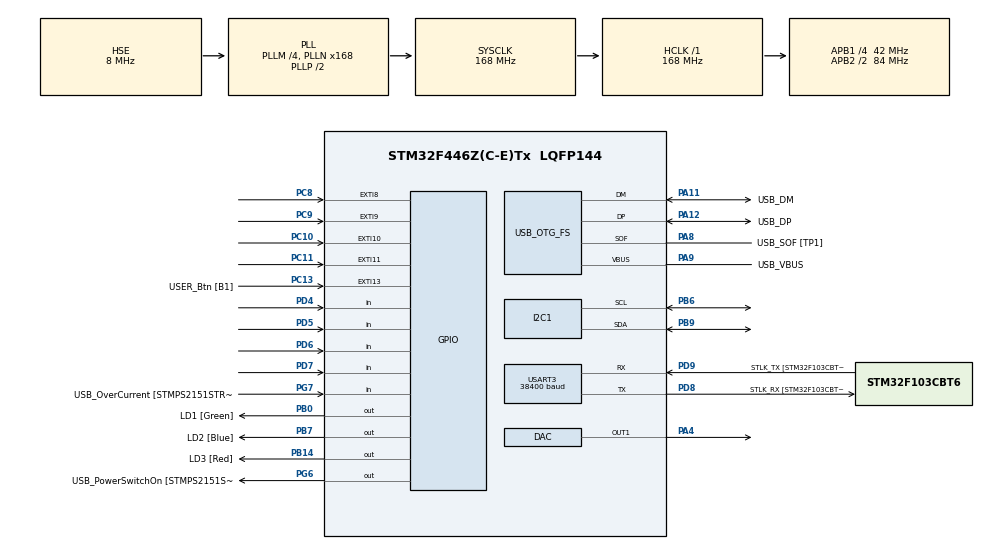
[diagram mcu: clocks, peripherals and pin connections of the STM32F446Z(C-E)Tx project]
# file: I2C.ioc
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Mcu.Family=STM32F4
Mcu.Name=STM32F446Z(C-E)Tx
Mcu.Package=LQFP144
NVIC.PriorityGroup=NVIC_PRIORITYGROUP_4
PA10.GPIO_Label=USB_ID
PA10.Signal=USB_OTG_FS_ID
PA11.GPIO_Label=USB_DM
PA11.Mode=Device_Only
PA11.Signal=USB_OTG_FS_DM
PA12.GPIO_Label=USB_DP
PA12.Mode=Device_Only
PA12.Signal=USB_OTG_FS_DP
PA13.GPIO_Label=TMS
PA13.Mode=Serial_Wire
PA13.Signal=SYS_JTMS-SWDIO
PA14.GPIO_Label=TCK
PA14.Mode=Serial_Wire
PA14.Signal=SYS_JTCK-SWCLK
PA4.Signal=COMP_DAC1_group
PA8.GPIO_Label=USB_SOF [TP1]
PA8.Mode=Activate_SOF_FS
PA8.Signal=USB_OTG_FS_SOF
PA9.GPIO_Label=USB_VBUS
PA9.Mode=Activate_VBUS
PA9.Signal=USB_OTG_FS_VBUS
PB0.GPIO_Label=LD1 [Green]
PB0.Signal=GPIO_Output
PB14.GPIO_Label=LD3 [Red]
PB14.Signal=GPIO_Output
PB6.Mode=I2C
PB6.Signal=I2C1_SCL
PB7.GPIO_Label=LD2 [Blue]
PB7.Signal=GPIO_Output
PB9.Mode=I2C
PB9.Signal=I2C1_SDA
PC10.Signal=GPXTI10
PC11.Signal=GPXTI11
PC13.GPIO_Label=USER_Btn [B1]
PC13.Signal=GPXTI13
PC14-OSC32_IN.Mode=LSE-External-Oscillator
PC14-OSC32_IN.Signal=RCC_OSC32_IN
PC15-OSC32_OUT.Mode=LSE-External-Oscillator
PC15-OSC32_OUT.Signal=RCC_OSC32_OUT
PC8.Signal=GPXTI8
PC9.Signal=GPXTI9
PD4.Signal=GPIO_Input
PD5.Signal=GPIO_Input
PD6.Signal=GPIO_Input
PD7.Signal=GPIO_Input
PD8.GPIO_Label=STLK_RX [STM32F103CBT6_PA3]
PD8.Mode=Asynchronous
PD8.Signal=USART3_TX
PD9.GPIO_Label=STLK_TX [STM32F103CBT6_PA2]
PD9.Mode=Asynchronous
PD9.Signal=USART3_RX
PG6.GPIO_Label=USB_PowerSwitchOn [STMPS2151STR_EN]
PG6.Signal=GPIO_Output
PG7.GPIO_Label=USB_OverCurrent [STMPS2151STR_FAULT]
PG7.Signal=GPIO_Input
PH0-OSC_IN.GPIO_Label=MCO [STM32F103CBT6_PA8]
PH0-OSC_IN.Mode=HSE-External-Clock-Source
PH0-OSC_IN.Signal=RCC_OSC_IN
PH1-OSC_OUT.Mode=HSE-External-Clock-Source
PH1-OSC_OUT.Signal=RCC_OSC_OUT
ProjectManager.HeapSize=0x200
ProjectManager.StackSize=0x400
ProjectManager.TargetToolchain=STM32CubeIDE
RCC.48MHZClocksFreq_Value=24000000
RCC.AHBFreq_Value=168000000
RCC.APB1CLKDivider=RCC_HCLK_DIV4
RCC.APB1Freq_Value=42000000
RCC.APB1TimFreq_Value=84000000
RCC.APB2CLKDivider=RCC_HCLK_DIV2
RCC.APB2Freq_Value=84000000
RCC.APB2TimFreq_Value=168000000
RCC.CortexFreq_Value=168000000
RCC.HCLKFreq_Value=168000000
RCC.HSE_VALUE=8000000
RCC.HSI_VALUE=16000000
RCC.PLLM=4
RCC.PLLMUL=RCC_PLL_MUL9
RCC.PLLN=168
RCC.PLLQ=7
RCC.PRESCALERUSB=RCC_USBCLKSOURCE_PLL_DIV1_5
RCC.SYSCLKFreq_VALUE=168000000
RCC.SYSCLKSource=RCC_SYSCLKSOURCE_PLLCLK
RCC.SYSCLKSourceVirtual=RCC_SYSCLKSOURCE_PLLCLK
RCC.USBFreq_Value=48000000
RCC.VCOOutputFreq_Value=336000000
SH.COMP_DAC1_group.0=DAC_OUT1,DAC_OUT1
USART3.BaudRate=38400
USART3.VirtualMode=VM_ASYNC
USB_OTG_FS.VirtualMode=Device_Only
VP_TIM6_VS_ClockSourceINT.Mode=Enable_Timer
board=NUCLEO-F446ZE

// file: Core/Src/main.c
/* USER CODE BEGIN Header */
/**
  ******************************************************************************
  * @file           : main.c
  * @brief          : Main program body
  ******************************************************************************
  * @attention
  *
  * Copyright (c) 2025 STMicroelectronics.
  * All rights reserved.
  *
  * This software is licensed under terms that can be found in the LICENSE file
  * in the root directory of this software component.
  * If no LICENSE file comes with this software, it is provided AS-IS.
  *
  ******************************************************************************
  */
/* USER CODE END Header */
#include "main.h"

/* USER CODE BEGIN Includes */
#include "TPA2016D2.h"

#include <stdio.h>
#include <string.h>
#include "twinkle_twinkle.h"
/* USER CODE END Includes */

DAC_HandleTypeDef hdac;

I2C_HandleTypeDef hi2c1;

TIM_HandleTypeDef htim6;

UART_HandleTypeDef huart3;

PCD_HandleTypeDef hpcd_USB_OTG_FS;

/* USER CODE BEGIN PV */
volatile int playback_index = 0;
/* USER CODE END PV */

void SystemClock_Config(void);
static void MX_GPIO_Init(void);
static void MX_I2C1_Init(void);
static void MX_USART3_UART_Init(void);
static void MX_USB_OTG_FS_PCD_Init(void);
static void MX_DAC_Init(void);
static void MX_TIM6_Init(void);
/* USER CODE BEGIN PFP */
char message[100];

int8_t current_row = -1, current_col = -1;
int which;
int direction = 1;
int tempo = 1;
int start = 0;
int end = 40016;

/* USER CODE END PFP */

/* USER CODE BEGIN 0 */
void HAL_TIM_PeriodElapsedCallback(TIM_HandleTypeDef *htim)
{
    if (htim->Instance == TIM6)
    {
        HAL_DAC_SetValue(&hdac, DAC_CHANNEL_2, DAC_ALIGN_8B_R, audio_data[playback_index]);
        //sprintf(message, "sending %d\n", audio_data[playback_index]);
        //print_msg(message);
        playback_index = (playback_index+direction) % end;
    }
}

/* USER CODE END 0 */

int main(void)
{

  /* MCU Configuration--------------------------------------------------------*/

  /* Reset of all peripherals, Initializes the Flash interface and the Systick. */
  HAL_Init();

  /* USER CODE BEGIN Init */
	HAL_Init();
	SystemClock_Config();

	MX_GPIO_Init();
	MX_DAC_Init();
	MX_TIM6_Init();     // Must include HAL_TIM_Base_Start_IT() in it
	MX_USART3_UART_Init();
	MX_USB_OTG_FS_PCD_Init();
	MX_I2C1_Init();
  /* USER CODE END Init */

  /* Initialize all configured peripherals */

  /* USER CODE BEGIN 2 */
	HAL_DAC_Start(&hdac, DAC_CHANNEL_2);  // Start DAC channel

  print_msg("finished setup");

  /* USER CODE END 2 */

  /* Infinite loop */
  while (1)
  {

    /* USER CODE BEGIN 3 */

	HAL_GPIO_WritePin(ROW0_GPIO_Port, ROW0_Pin, GPIO_PIN_SET);
	which = 0;
	HAL_GPIO_WritePin(ROW1_GPIO_Port, ROW1_Pin, GPIO_PIN_RESET);
	HAL_GPIO_WritePin(ROW2_GPIO_Port, ROW2_Pin, GPIO_PIN_RESET);
	HAL_GPIO_WritePin(ROW3_GPIO_Port, ROW3_Pin, GPIO_PIN_RESET);
	HAL_Delay(50);

	HAL_GPIO_WritePin(ROW0_GPIO_Port, ROW0_Pin, GPIO_PIN_RESET);
	which = 1;
	HAL_GPIO_WritePin(ROW1_GPIO_Port, ROW1_Pin, GPIO_PIN_SET);
	HAL_GPIO_WritePin(ROW2_GPIO_Port, ROW2_Pin, GPIO_PIN_RESET);
	HAL_GPIO_WritePin(ROW3_GPIO_Port, ROW3_Pin, GPIO_PIN_RESET);
	HAL_Delay(50);

	HAL_GPIO_WritePin(ROW0_GPIO_Port, ROW0_Pin, GPIO_PIN_RESET);
	which = 2;
	HAL_GPIO_WritePin(ROW1_GPIO_Port, ROW1_Pin, GPIO_PIN_RESET);
	HAL_GPIO_WritePin(ROW2_GPIO_Port, ROW2_Pin, GPIO_PIN_SET);
	HAL_GPIO_WritePin(ROW3_GPIO_Port, ROW3_Pin, GPIO_PIN_RESET);
	HAL_Delay(50);

	HAL_GPIO_WritePin(ROW0_GPIO_Port, ROW0_Pin, GPIO_PIN_RESET);
	which = 3;
	HAL_GPIO_WritePin(ROW1_GPIO_Port, ROW1_Pin, GPIO_PIN_RESET);
	HAL_GPIO_WritePin(ROW2_GPIO_Port, ROW2_Pin, GPIO_PIN_RESET);
	HAL_GPIO_WritePin(ROW3_GPIO_Port, ROW3_Pin, GPIO_PIN_SET);
	HAL_Delay(50);

  }
  /* USER CODE END 3 */
}

void SystemClock_Config(void)
{
  RCC_OscInitTypeDef RCC_OscInitStruct = {0};
  RCC_ClkInitTypeDef RCC_ClkInitStruct = {0};

  /** Configure the main internal regulator output voltage
  */
  __HAL_RCC_PWR_CLK_ENABLE();
  __HAL_PWR_VOLTAGESCALING_CONFIG(PWR_REGULATOR_VOLTAGE_SCALE1);

  /** Initializes the RCC Oscillators according to the specified parameters
  * in the RCC_OscInitTypeDef structure.
  */
  RCC_OscInitStruct.OscillatorType = RCC_OSCILLATORTYPE_HSE;
  RCC_OscInitStruct.HSEState = RCC_HSE_BYPASS;
  RCC_OscInitStruct.PLL.PLLState = RCC_PLL_ON;
  RCC_OscInitStruct.PLL.PLLSource = RCC_PLLSOURCE_HSE;
  RCC_OscInitStruct.PLL.PLLM = 4;
  RCC_OscInitStruct.PLL.PLLN = 168;
  RCC_OscInitStruct.PLL.PLLP = RCC_PLLP_DIV2;
  RCC_OscInitStruct.PLL.PLLQ = 7;
  RCC_OscInitStruct.PLL.PLLR = 2;
  if (HAL_RCC_OscConfig(&RCC_OscInitStruct) != HAL_OK)
  {
    Error_Handler();
  }

  /** Initializes the CPU, AHB and APB buses clocks
  */
  RCC_ClkInitStruct.ClockType = RCC_CLOCKTYPE_HCLK|RCC_CLOCKTYPE_SYSCLK
                              |RCC_CLOCKTYPE_PCLK1|RCC_CLOCKTYPE_PCLK2;
  RCC_ClkInitStruct.SYSCLKSource = RCC_SYSCLKSOURCE_PLLCLK;
  RCC_ClkInitStruct.AHBCLKDivider = RCC_SYSCLK_DIV1;
  RCC_ClkInitStruct.APB1CLKDivider = RCC_HCLK_DIV4;
  RCC_ClkInitStruct.APB2CLKDivider = RCC_HCLK_DIV2;

  if (HAL_RCC_ClockConfig(&RCC_ClkInitStruct, FLASH_LATENCY_5) != HAL_OK)
  {
    Error_Handler();
  }
}

static void MX_DAC_Init(void)
{

  DAC_ChannelConfTypeDef sConfig = {0};

  /** DAC Initialization
  */
  hdac.Instance = DAC;
  if (HAL_DAC_Init(&hdac) != HAL_OK)
  {
    Error_Handler();
  }

  /** DAC channel OUT1 config
  */
  sConfig.DAC_Trigger = DAC_TRIGGER_NONE;
  sConfig.DAC_OutputBuffer = DAC_OUTPUTBUFFER_ENABLE;
  if (HAL_DAC_ConfigChannel(&hdac, &sConfig, DAC_CHANNEL_2) != HAL_OK)
  {
    Error_Handler();
  }

}

static void MX_I2C1_Init(void)
{

  hi2c1.Instance = I2C1;
  hi2c1.Init.ClockSpeed = 100000;
  hi2c1.Init.DutyCycle = I2C_DUTYCYCLE_2;
  hi2c1.Init.OwnAddress1 = 0;
  hi2c1.Init.AddressingMode = I2C_ADDRESSINGMODE_7BIT;
  hi2c1.Init.DualAddressMode = I2C_DUALADDRESS_DISABLE;
  hi2c1.Init.OwnAddress2 = 0;
  hi2c1.Init.GeneralCallMode = I2C_GENERALCALL_DISABLE;
  hi2c1.Init.NoStretchMode = I2C_NOSTRETCH_DISABLE;
  if (HAL_I2C_Init(&hi2c1) != HAL_OK)
  {
    Error_Handler();
  }

}

static void MX_TIM6_Init(void)
{

  TIM_MasterConfigTypeDef sMasterConfig = {0};

  htim6.Instance = TIM6;
  htim6.Init.Prescaler = 84-1;
  htim6.Init.CounterMode = TIM_COUNTERMODE_UP;
  htim6.Init.Period = (125-1)*tempo;
  htim6.Init.AutoReloadPreload = TIM_AUTORELOAD_PRELOAD_DISABLE;
  if (HAL_TIM_Base_Init(&htim6) != HAL_OK)
  {
    Error_Handler();
  }
  sMasterConfig.MasterOutputTrigger = TIM_TRGO_RESET;
  sMasterConfig.MasterSlaveMode = TIM_MASTERSLAVEMODE_DISABLE;
  if (HAL_TIMEx_MasterConfigSynchronization(&htim6, &sMasterConfig) != HAL_OK)
  {
    Error_Handler();
  }
  /* USER CODE BEGIN TIM6_Init 2 */
	HAL_NVIC_SetPriority(TIM6_DAC_IRQn, 0, 0);
	HAL_NVIC_EnableIRQ(TIM6_DAC_IRQn);
  /* USER CODE END TIM6_Init 2 */

}

static void MX_USART3_UART_Init(void)
{

  huart3.Instance = USART3;
  huart3.Init.BaudRate = 38400;
  huart3.Init.WordLength = UART_WORDLENGTH_8B;
  huart3.Init.StopBits = UART_STOPBITS_1;
  huart3.Init.Parity = UART_PARITY_NONE;
  huart3.Init.Mode = UART_MODE_TX_RX;
  huart3.Init.HwFlowCtl = UART_HWCONTROL_NONE;
  huart3.Init.OverSampling = UART_OVERSAMPLING_16;
  if (HAL_UART_Init(&huart3) != HAL_OK)
  {
    Error_Handler();
  }

}

static void MX_USB_OTG_FS_PCD_Init(void)
{

  hpcd_USB_OTG_FS.Instance = USB_OTG_FS;
  hpcd_USB_OTG_FS.Init.dev_endpoints = 6;
  hpcd_USB_OTG_FS.Init.speed = PCD_SPEED_FULL;
  hpcd_USB_OTG_FS.Init.dma_enable = DISABLE;
  hpcd_USB_OTG_FS.Init.phy_itface = PCD_PHY_EMBEDDED;
  hpcd_USB_OTG_FS.Init.Sof_enable = ENABLE;
  hpcd_USB_OTG_FS.Init.low_power_enable = DISABLE;
  hpcd_USB_OTG_FS.Init.lpm_enable = DISABLE;
  hpcd_USB_OTG_FS.Init.vbus_sensing_enable = ENABLE;
  hpcd_USB_OTG_FS.Init.use_dedicated_ep1 = DISABLE;
  if (HAL_PCD_Init(&hpcd_USB_OTG_FS) != HAL_OK)
  {
    Error_Handler();
  }

}

static void MX_GPIO_Init(void)
{
	GPIO_InitTypeDef GPIO_InitStruct = {0};

	  /* GPIO Ports Clock Enable */
	  __HAL_RCC_GPIOC_CLK_ENABLE();
	  __HAL_RCC_GPIOH_CLK_ENABLE();
	  __HAL_RCC_GPIOB_CLK_ENABLE();
	  __HAL_RCC_GPIOD_CLK_ENABLE();
	  __HAL_RCC_GPIOG_CLK_ENABLE();
	  __HAL_RCC_GPIOA_CLK_ENABLE();

	  /*Configure GPIO pin Output Level */
	  HAL_GPIO_WritePin(GPIOB, LD1_Pin|LD3_Pin|LD2_Pin, GPIO_PIN_RESET);

	  /*Configure GPIO pin Output Level */
	  HAL_GPIO_WritePin(USB_PowerSwitchOn_GPIO_Port, USB_PowerSwitchOn_Pin, GPIO_PIN_RESET);

	  /*Configure GPIO pin Output Level */
	  HAL_GPIO_WritePin(GPIOC, ROW0_Pin|ROW1_Pin|ROW2_Pin|ROW3_Pin, GPIO_PIN_RESET);

	  /*Configure GPIO pin : USER_Btn_Pin */
	  GPIO_InitStruct.Pin = USER_Btn_Pin;
	  GPIO_InitStruct.Mode = GPIO_MODE_IT_RISING;
	  GPIO_InitStruct.Pull = GPIO_NOPULL;
	  HAL_GPIO_Init(USER_Btn_GPIO_Port, &GPIO_InitStruct);

	  /*Configure GPIO pins : LD1_Pin LD3_Pin LD2_Pin */
	  GPIO_InitStruct.Pin = LD1_Pin|LD3_Pin|LD2_Pin;
	  GPIO_InitStruct.Mode = GPIO_MODE_OUTPUT_PP;
	  GPIO_InitStruct.Pull = GPIO_NOPULL;
	  GPIO_InitStruct.Speed = GPIO_SPEED_FREQ_LOW;
	  HAL_GPIO_Init(GPIOB, &GPIO_InitStruct);

	  /*Configure GPIO pin : USB_PowerSwitchOn_Pin */
	  GPIO_InitStruct.Pin = USB_PowerSwitchOn_Pin;
	  GPIO_InitStruct.Mode = GPIO_MODE_OUTPUT_PP;
	  GPIO_InitStruct.Pull = GPIO_NOPULL;
	  GPIO_InitStruct.Speed = GPIO_SPEED_FREQ_LOW;
	  HAL_GPIO_Init(USB_PowerSwitchOn_GPIO_Port, &GPIO_InitStruct);

	  /*Configure GPIO pin : USB_OverCurrent_Pin */
	  GPIO_InitStruct.Pin = USB_OverCurrent_Pin;
	  GPIO_InitStruct.Mode = GPIO_MODE_INPUT;
	  GPIO_InitStruct.Pull = GPIO_NOPULL;
	  HAL_GPIO_Init(USB_OverCurrent_GPIO_Port, &GPIO_InitStruct);

	  /*Configure GPIO pins : ROW0_Pin ROW1_Pin ROW2_Pin ROW3_Pin */
	  GPIO_InitStruct.Pin = ROW0_Pin|ROW1_Pin|ROW2_Pin|ROW3_Pin;
	  GPIO_InitStruct.Mode = GPIO_MODE_OUTPUT_PP;
	  GPIO_InitStruct.Pull = GPIO_NOPULL;
	  GPIO_InitStruct.Speed = GPIO_SPEED_FREQ_LOW;
	  HAL_GPIO_Init(GPIOC, &GPIO_InitStruct);

	  /*Configure GPIO pins : COL0_Pin COL1_Pin COL2_Pin COL3_Pin */
	  GPIO_InitStruct.Pin = COL0_Pin|COL1_Pin|COL2_Pin|COL3_Pin;
	  GPIO_InitStruct.Mode = GPIO_MODE_IT_RISING;
	  GPIO_InitStruct.Pull = GPIO_PULLDOWN;
	  HAL_GPIO_Init(GPIOD, &GPIO_InitStruct);

	  /* EXTI interrupt init*/
	  HAL_NVIC_SetPriority(EXTI4_IRQn, 1, 0);
	  HAL_NVIC_EnableIRQ(EXTI4_IRQn);

	  HAL_NVIC_SetPriority(EXTI9_5_IRQn, 1, 0);
	  HAL_NVIC_EnableIRQ(EXTI9_5_IRQn);

}

/* USER CODE BEGIN 4 */
void print_msg(char * msg) {
  HAL_UART_Transmit(&huart3, (uint8_t *)msg, strlen(msg), 100);
}

/* USER CODE END 4 */

void Error_Handler(void)
{
  /* USER CODE BEGIN Error_Handler_Debug */
  /* User can add his own implementation to report the HAL error return state */
  __disable_irq();
  sprintf(message, "error!!");
  print_msg(message);

  while (1)
  {
  }
  /* USER CODE END Error_Handler_Debug */
}
